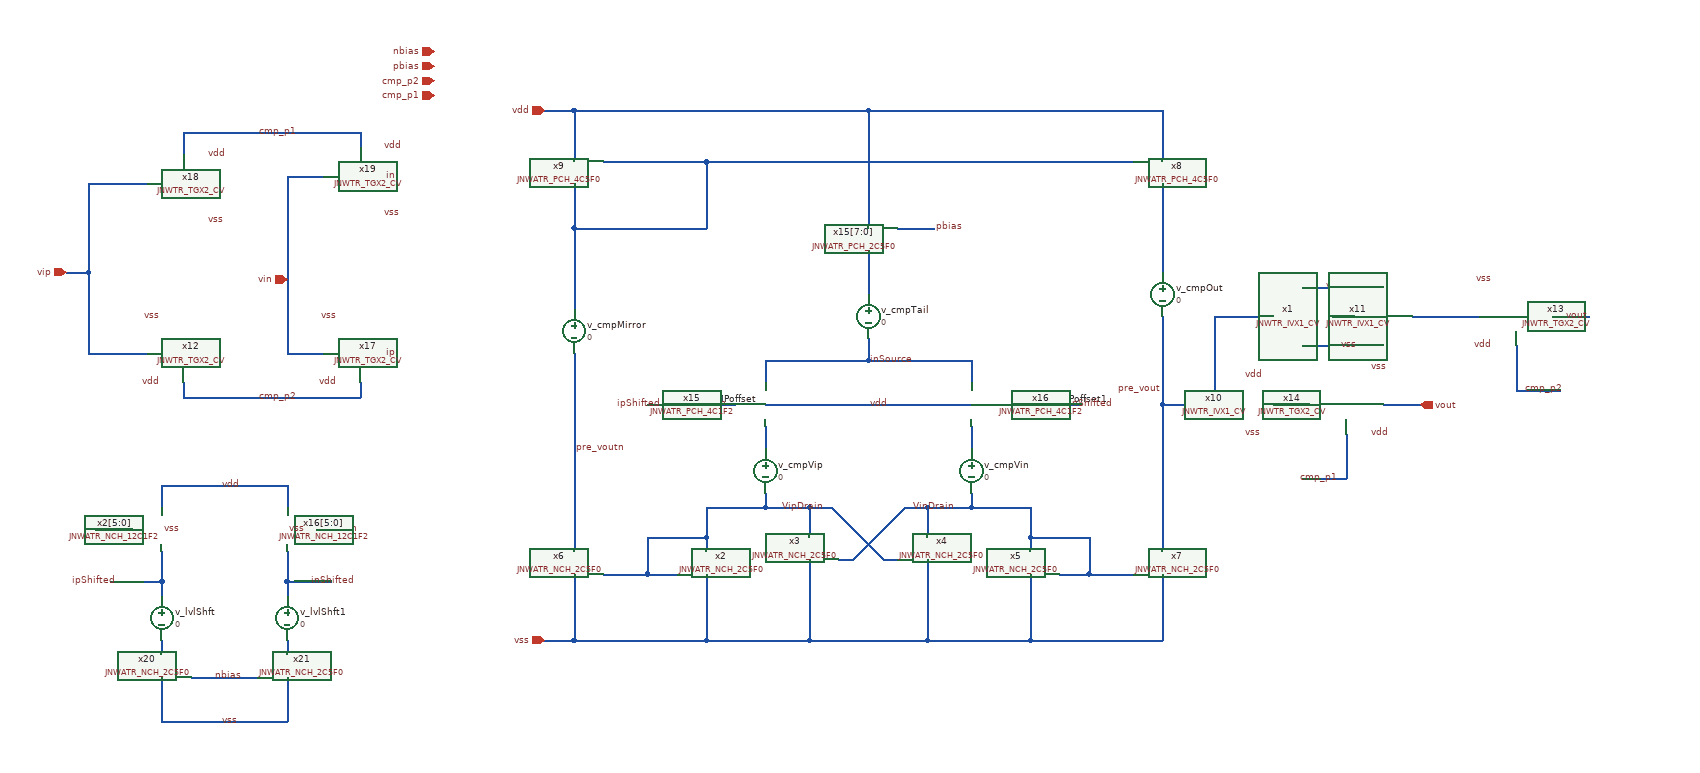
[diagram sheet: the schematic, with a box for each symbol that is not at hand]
v {xschem version=3.4.6 file_version=1.2}
G {}
K {}
V {}
S {}
E {}
N 1230 -690 1230 -650 {
lab=VipDrain}
N 1310 -690 1370 -690 {
lab=VipDrain}
N 1370 -690 1370 -650 {
lab=VipDrain}
N 1530 -690 1530 -650 {
lab=VinDrain}
N 1590 -690 1670 -690 {
lab=VinDrain}
N 1670 -650 1670 -630 {
lab=VinDrain}
N 1410 -620 1430 -620 {
lab=VinDrain}
N 1430 -620 1500 -690 {
lab=VinDrain}
N 1470 -620 1490 -620 {
lab=VipDrain}
N 1400 -690 1470 -620 {
lab=VipDrain}
N 1370 -690 1400 -690 {
lab=VipDrain}
N 1500 -690 1530 -690 {
lab=VinDrain}
N 1370 -620 1370 -510 {
lab=vss}
N 1530 -620 1530 -510 {
lab=vss}
N 1670 -510 1850 -510 {
lab=vss}
N 1230 -510 1370 -510 {
lab=vss}
N 1370 -510 1530 -510 {
lab=vss}
N 1530 -510 1670 -510 {
lab=vss}
N 1670 -600 1670 -510 {
lab=vss}
N 1230 -600 1230 -510 {
lab=vss}
N 1150 -600 1190 -600 {
lab=VipDrain}
N 1150 -650 1230 -650 {
lab=VipDrain}
N 1150 -650 1150 -600 {
lab=VipDrain}
N 1090 -600 1150 -600 {
lab=VipDrain}
N 1230 -650 1230 -630 {
lab=VipDrain}
N 1750 -650 1750 -600 {
lab=VinDrain}
N 1670 -650 1750 -650 {
lab=VinDrain}
N 1670 -690 1670 -650 {
lab=VinDrain}
N 1710 -600 1750 -600 {
lab=VinDrain}
N 1050 -600 1050 -510 {
lab=vss}
N 1850 -600 1850 -510 {
lab=vss}
N 1850 -830 1850 -630 {
lab=pre_vout}
N 1750 -600 1810 -600 {
lab=VinDrain}
N 1230 -1160 1230 -1070 {
lab=#net1}
N 1090 -1160 1230 -1160 {
lab=#net1}
N 1050 -1230 1050 -1160 {
lab=vdd}
N 1850 -1230 1850 -1160 {
lab=vdd}
N 1010 -1230 1050 -1230 {
lab=vdd}
N 1050 -510 1230 -510 {
lab=vss}
N 1010 -510 1050 -510 {
lab=vss}
N 1850 -830 1920 -830 {
lab=pre_vout}
N 1310 -890 1310 -860 {
lab=inSource}
N 1590 -890 1590 -860 {
lab=inSource}
N 1450 -1230 1850 -1230 {
lab=vdd}
N 1050 -1070 1230 -1070 {
lab=#net1}
N 1050 -1130 1050 -1070 {
lab=#net1}
N 1230 -1160 1810 -1160 {
lab=#net1}
N 2000 -830 2050 -830 {
lab=#net2}
N 2100 -790 2100 -730 {
lab=cmp_p1}
N 2040 -730 2100 -730 {
lab=cmp_p1}
N 2150 -830 2200 -830 {
lab=vout}
N 390 -1010 390 -900 {
lab=vip}
N 390 -1130 470 -1130 {
lab=vip}
N 390 -900 470 -900 {
lab=vip}
N 660 -1140 660 -900 {
lab=vin}
N 660 -1140 710 -1140 {
lab=vin}
N 660 -900 710 -900 {
lab=vin}
N 520 -860 520 -840 {
lab=cmp_p2}
N 520 -840 760 -840 {
lab=cmp_p2}
N 760 -860 760 -840 {
lab=cmp_p2}
N 520 -1200 520 -1170 {
lab=cmp_p1}
N 520 -1200 760 -1200 {
lab=cmp_p1}
N 760 -1200 760 -1180 {
lab=cmp_p1}
N 1450 -1230 1450 -1070 {lab=vdd}
N 1050 -1230 1450 -1230 {
lab=vdd}
N 1450 -920 1450 -890 {lab=inSource}
N 1150 -830 1180 -830 {lab=ipShifted}
N 1240 -830 1270 -830 {lab=ipm}
N 1920 -950 1920 -830 {lab=pre_vout}
N 1920 -950 2000 -950 {lab=pre_vout}
N 2040 -910 2150 -910 {lab=vss}
N 2330 -910 2330 -850 {
lab=cmp_p2}
N 2330 -850 2390 -850 {
lab=cmp_p2}
N 2380 -950 2430 -950 {lab=vout}
N 2190 -950 2280 -950 {lab=#net3}
N 2080 -950 2110 -950 {lab=#net4}
N 2040 -990 2150 -990 {lab=vdd}
N 390 -1130 390 -1010 {
lab=vip}
N 1630 -830 1650 -830 {lab=#net5}
N 1710 -830 1740 -830 {lab=inShifted}
N 1050 -1070 1050 -960 {lab=#net1}
N 1050 -900 1050 -630 {lab=pre_voutn}
N 1850 -1130 1850 -1010 {lab=#net6}
N 1850 -950 1850 -830 {lab=pre_vout}
N 1590 -800 1590 -770 {lab=#net7}
N 1590 -710 1590 -690 {lab=VinDrain}
N 1530 -690 1590 -690 {
lab=VinDrain}
N 1310 -800 1310 -770 {lab=#net8}
N 1310 -710 1310 -690 {lab=VipDrain}
N 1230 -690 1310 -690 {
lab=VipDrain}
N 1490 -1070 1540 -1070 {lab=pbias}
N 1450 -1040 1450 -980 {lab=#net9}
N 400 -660 450 -660 {lab=ip}
N 1310 -890 1450 -890 {
lab=inSource}
N 1450 -890 1590 -890 {
lab=inSource}
N 1310 -830 1590 -830 {lab=vdd}
N 490 -720 660 -720 {lab=vdd}
N 490 -720 490 -690 {lab=vdd}
N 660 -720 660 -690 {lab=vdd}
N 530 -460 620 -460 {lab=nbias}
N 700 -660 740 -660 {lab=in}
N 660 -460 660 -400 {lab=vss}
N 490 -400 660 -400 {lab=vss}
N 490 -460 490 -400 {lab=vss}
N 420 -590 490 -590 {lab=ipShifted}
N 660 -590 720 -590 {lab=inShifted}
N 660 -630 660 -590 {lab=inShifted}
N 490 -630 490 -590 {lab=ipShifted}
N 660 -590 660 -570 {lab=inShifted}
N 660 -510 660 -490 {lab=#net10}
N 490 -590 490 -570 {lab=ipShifted}
N 490 -510 490 -490 {lab=#net11}
N 360 -1010 390 -1010 {lab=vip}
C {devices/ipin.sym} 1010 -510 0 0 {name=p2 lab=vss
}
C {devices/ipin.sym} 1010 -1230 0 0 {name=p3 lab=vdd
}
C {devices/ipin.sym} 860 -1290 0 0 {name=p1 lab=pbias
}
C {devices/ipin.sym} 660 -1000 0 0 {name=p5 lab=vin
}
C {devices/ipin.sym} 360 -1010 0 0 {name=p6 lab=vip
}
C {JNW_ATR_SKY130A/JNWATR_NCH_2C5F0.sym} 1190 -600 0 0 {name=x2 }
C {JNW_ATR_SKY130A/JNWATR_NCH_2C5F0.sym} 1410 -620 0 1 {name=x3 }
C {JNW_ATR_SKY130A/JNWATR_NCH_2C5F0.sym} 1490 -620 0 0 {name=x4 }
C {JNW_ATR_SKY130A/JNWATR_NCH_2C5F0.sym} 1710 -600 0 1 {name=x5 }
C {JNW_ATR_SKY130A/JNWATR_NCH_2C5F0.sym} 1090 -600 0 1 {name=x6 }
C {JNW_ATR_SKY130A/JNWATR_NCH_2C5F0.sym} 1810 -600 0 0 {name=x7 }
C {JNW_ATR_SKY130A/JNWATR_PCH_4C5F0.sym} 1810 -1160 0 0 {name=x8 }
C {JNW_ATR_SKY130A/JNWATR_PCH_4C5F0.sym} 1090 -1160 0 1 {name=x9 }
C {devices/opin.sym} 2200 -830 0 0 {name=p7 lab=vout}
C {JNW_TR_SKY130A/JNWTR_IVX1_CV.sym} 1920 -830 0 0 {name=x10 }
C {devices/ipin.sym} 860 -1250 0 0 {name=p10 lab=cmp_p1
}
C {devices/lab_wire.sym} 2070 -990 0 1 {name=p18 sig_type=std_logic lab=vdd}
C {devices/lab_wire.sym} 1960 -790 0 1 {name=p19 sig_type=std_logic lab=vss}
C {JNW_TR_SKY130A/JNWTR_TGX2_CV.sym} 2040 -830 2 1 {name=x14 }
C {devices/lab_wire.sym} 2130 -790 0 1 {name=p20 sig_type=std_logic lab=vdd}
C {devices/lab_wire.sym} 2130 -880 0 1 {name=p21 sig_type=std_logic lab=vss}
C {devices/lab_wire.sym} 2090 -730 0 0 {name=p22 sig_type=std_logic lab=cmp_p1}
C {devices/lab_wire.sym} 570 -900 0 0 {name=p32 sig_type=std_logic lab=in}
C {devices/lab_wire.sym} 570 -1130 0 0 {name=p33 sig_type=std_logic lab=ip}
C {devices/lab_wire.sym} 420 -660 0 0 {name=p34 sig_type=std_logic lab=ip}
C {devices/lab_wire.sym} 740 -660 0 1 {name=p35 sig_type=std_logic lab=in}
C {devices/ipin.sym} 860 -1270 0 0 {name=p11 lab=cmp_p2
}
C {devices/lab_wire.sym} 1570 -690 0 0 {name=p12 sig_type=std_logic lab=VinDrain}
C {devices/lab_wire.sym} 1330 -690 0 1 {name=p13 sig_type=std_logic lab=VipDrain}
C {devices/lab_wire.sym} 1050 -770 0 1 {name=p37 sig_type=std_logic lab=pre_voutn}
C {devices/lab_wire.sym} 1850 -850 0 0 {name=p38 sig_type=std_logic lab=pre_vout}
C {JNW_TR_SKY130A/JNWTR_TGX2_CV.sym} 580 -900 2 0 {name=x12 }
C {devices/lab_wire.sym} 490 -860 0 0 {name=p29 sig_type=std_logic lab=vdd}
C {devices/lab_wire.sym} 490 -950 0 0 {name=p30 sig_type=std_logic lab=vss}
C {JNW_TR_SKY130A/JNWTR_TGX2_CV.sym} 820 -900 2 0 {name=x17 }
C {devices/lab_wire.sym} 730 -860 0 0 {name=p31 sig_type=std_logic lab=vdd}
C {devices/lab_wire.sym} 730 -950 0 0 {name=p36 sig_type=std_logic lab=vss}
C {JNW_TR_SKY130A/JNWTR_TGX2_CV.sym} 460 -1130 0 0 {name=x18 }
C {devices/lab_wire.sym} 550 -1170 2 0 {name=p39 sig_type=std_logic lab=vdd}
C {devices/lab_wire.sym} 550 -1080 2 0 {name=p40 sig_type=std_logic lab=vss}
C {JNW_TR_SKY130A/JNWTR_TGX2_CV.sym} 700 -1140 0 0 {name=x19 }
C {devices/lab_wire.sym} 790 -1180 2 0 {name=p41 sig_type=std_logic lab=vdd}
C {devices/lab_wire.sym} 790 -1090 2 0 {name=p42 sig_type=std_logic lab=vss}
C {devices/lab_wire.sym} 810 -900 0 0 {name=p43 sig_type=std_logic lab=ip}
C {devices/lab_wire.sym} 810 -1140 0 0 {name=p44 sig_type=std_logic lab=in}
C {devices/lab_wire.sym} 620 -840 0 1 {name=p45 sig_type=std_logic lab=cmp_p2}
C {devices/lab_wire.sym} 620 -1200 0 1 {name=p46 sig_type=std_logic lab=cmp_p1}
C {JNW_ATR_SKY130A/JNWATR_PCH_2C5F0.sym} 1490 -1070 0 1 {name=x15[7:0]}
C {devices/vsource.sym} 1450 -950 0 0 {name=v_cmpTail value=0 savecurrent=true}
C {devices/lab_wire.sym} 1450 -890 0 1 {name=p47 sig_type=std_logic lab=inSource}
C {devices/vsource.sym} 1210 -830 1 0 {name=vCMPoffset value=0 savecurrent=false}
C {JNW_TR_SKY130A/JNWTR_IVX1_CV.sym} 2000 -950 0 0 {name=x1 }
C {JNW_TR_SKY130A/JNWTR_IVX1_CV.sym} 2110 -950 0 0 {name=x11 }
C {devices/lab_wire.sym} 1960 -870 0 1 {name=p48 sig_type=std_logic lab=vdd}
C {devices/lab_wire.sym} 2090 -910 0 1 {name=p49 sig_type=std_logic lab=vss}
C {JNW_TR_SKY130A/JNWTR_TGX2_CV.sym} 2390 -950 2 0 {name=x13 }
C {devices/lab_wire.sym} 2300 -910 0 0 {name=p51 sig_type=std_logic lab=vdd}
C {devices/lab_wire.sym} 2300 -1000 0 0 {name=p52 sig_type=std_logic lab=vss}
C {devices/lab_wire.sym} 2340 -850 0 1 {name=p53 sig_type=std_logic lab=cmp_p2}
C {devices/lab_wire.sym} 2430 -950 0 0 {name=p54 sig_type=std_logic lab=vout}
C {devices/lab_wire.sym} 1260 -830 0 0 {name=p8 sig_type=std_logic lab=ipm}
C {devices/vsource.sym} 1680 -830 1 0 {name=vCMPoffset1 value=0 savecurrent=false}
C {devices/vsource.sym} 1050 -930 0 0 {name=v_cmpMirror value=0 savecurrent=true}
C {devices/vsource.sym} 1850 -980 0 0 {name=v_cmpOut value=0 savecurrent=true}
C {devices/vsource.sym} 1590 -740 0 0 {name=v_cmpVin value=0 savecurrent=true}
C {devices/vsource.sym} 1310 -740 0 0 {name=v_cmpVip value=0 savecurrent=true}
C {devices/lab_wire.sym} 1540 -1070 0 1 {name=p23 sig_type=std_logic lab=pbias}
C {devices/ipin.sym} 860 -1310 0 0 {name=p9 lab=nbias
}
C {JNW_ATR_SKY130A/JNWATR_NCH_12C1F2.sym} 450 -660 0 0 {name=x2[5:0]}
C {JNW_ATR_SKY130A/JNWATR_NCH_12C1F2.sym} 700 -660 0 1 {name=x16[5:0]}
C {devices/lab_wire.sym} 660 -660 0 1 {name=p14 sig_type=std_logic lab=vss}
C {devices/lab_wire.sym} 490 -660 0 1 {name=p15 sig_type=std_logic lab=vss}
C {JNW_ATR_SKY130A/JNWATR_PCH_4C1F2.sym} 1270 -830 0 0 {name=x15}
C {devices/lab_wire.sym} 1450 -830 0 1 {name=p4 sig_type=std_logic lab=vdd}
C {devices/lab_wire.sym} 570 -720 0 1 {name=p16 sig_type=std_logic lab=vdd}
C {JNW_ATR_SKY130A/JNWATR_NCH_2C5F0.sym} 530 -460 0 1 {name=x20 }
C {JNW_ATR_SKY130A/JNWATR_NCH_2C5F0.sym} 620 -460 0 0 {name=x21 }
C {devices/lab_wire.sym} 570 -400 0 1 {name=p17 sig_type=std_logic lab=vss}
C {devices/lab_wire.sym} 560 -460 0 1 {name=p24 sig_type=std_logic lab=nbias}
C {devices/lab_wire.sym} 430 -590 0 0 {name=p25 sig_type=std_logic lab=ipShifted}
C {devices/lab_wire.sym} 690 -590 0 1 {name=p26 sig_type=std_logic lab=inShifted}
C {devices/lab_wire.sym} 1720 -830 0 1 {name=p27 sig_type=std_logic lab=inShifted}
C {devices/lab_wire.sym} 1170 -830 0 0 {name=p28 sig_type=std_logic lab=ipShifted}
C {devices/vsource.sym} 490 -540 0 0 {name=v_lvlShft value=0 savecurrent=true}
C {devices/vsource.sym} 660 -540 0 0 {name=v_lvlShft1 value=0 savecurrent=true}
C {JNW_ATR_SKY130A/JNWATR_PCH_4C1F2.sym} 1630 -830 0 1 {name=x16}
